VERSION 5.7 ;
BUSBITCHARS "[]" ;
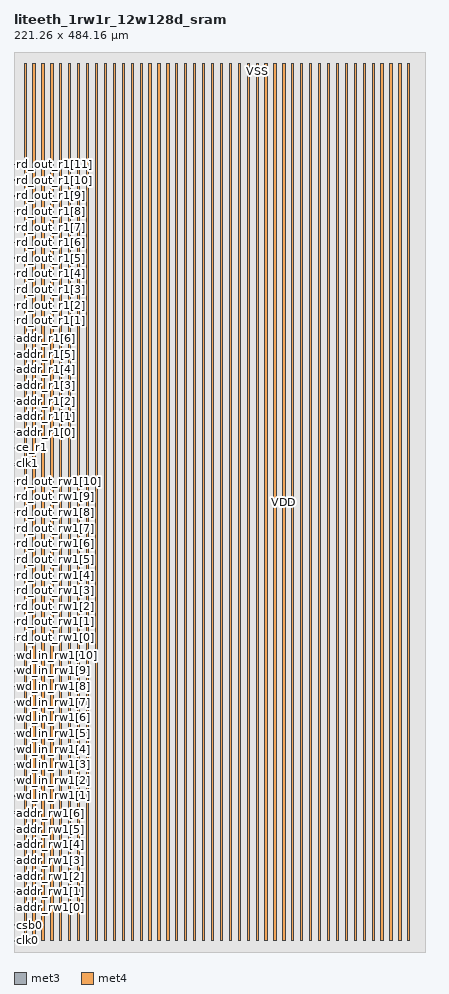
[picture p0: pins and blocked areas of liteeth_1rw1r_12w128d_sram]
MACRO liteeth_1rw1r_12w128d_sram
  FOREIGN liteeth_1rw1r_12w128d_sram 0 0 ;
  SYMMETRY X Y R90 ;
  SIZE 221.260 BY 484.160 ;
  CLASS BLOCK ;
  PIN clk0
    DIRECTION INPUT ;
    USE SIGNAL ;
    SHAPE ABUTMENT ;
    PORT
      LAYER met3 ;
      RECT 0.000 5.850 0.800 6.150 ;
    END
  END clk0
  PIN csb0
    DIRECTION INPUT ;
    USE SIGNAL ;
    SHAPE ABUTMENT ;
    PORT
      LAYER met3 ;
      RECT 0.000 14.250 0.800 14.550 ;
    END
  END csb0
  PIN we_in_rw1
    DIRECTION INPUT ;
    USE SIGNAL ;
    SHAPE ABUTMENT ;
    PORT
      LAYER met3 ;
      RECT 0.000 22.650 0.800 22.950 ;
    END
  END we_in_rw1
  PIN addr_rw1[0]
    DIRECTION INPUT ;
    USE SIGNAL ;
    SHAPE ABUTMENT ;
    PORT
      LAYER met3 ;
      RECT 0.000 23.850 0.800 24.150 ;
    END
  END addr_rw1[0]
  PIN addr_rw1[1]
    DIRECTION INPUT ;
    USE SIGNAL ;
    SHAPE ABUTMENT ;
    PORT
      LAYER met3 ;
      RECT 0.000 32.250 0.800 32.550 ;
    END
  END addr_rw1[1]
  PIN addr_rw1[2]
    DIRECTION INPUT ;
    USE SIGNAL ;
    SHAPE ABUTMENT ;
    PORT
      LAYER met3 ;
      RECT 0.000 40.650 0.800 40.950 ;
    END
  END addr_rw1[2]
  PIN addr_rw1[3]
    DIRECTION INPUT ;
    USE SIGNAL ;
    SHAPE ABUTMENT ;
    PORT
      LAYER met3 ;
      RECT 0.000 49.050 0.800 49.350 ;
    END
  END addr_rw1[3]
  PIN addr_rw1[4]
    DIRECTION INPUT ;
    USE SIGNAL ;
    SHAPE ABUTMENT ;
    PORT
      LAYER met3 ;
      RECT 0.000 57.450 0.800 57.750 ;
    END
  END addr_rw1[4]
  PIN addr_rw1[5]
    DIRECTION INPUT ;
    USE SIGNAL ;
    SHAPE ABUTMENT ;
    PORT
      LAYER met3 ;
      RECT 0.000 65.850 0.800 66.150 ;
    END
  END addr_rw1[5]
  PIN addr_rw1[6]
    DIRECTION INPUT ;
    USE SIGNAL ;
    SHAPE ABUTMENT ;
    PORT
      LAYER met3 ;
      RECT 0.000 74.250 0.800 74.550 ;
    END
  END addr_rw1[6]
  PIN wd_in_rw1[0]
    DIRECTION INPUT ;
    USE SIGNAL ;
    SHAPE ABUTMENT ;
    PORT
      LAYER met3 ;
      RECT 0.000 75.450 0.800 75.750 ;
    END
  END wd_in_rw1[0]
  PIN wd_in_rw1[1]
    DIRECTION INPUT ;
    USE SIGNAL ;
    SHAPE ABUTMENT ;
    PORT
      LAYER met3 ;
      RECT 0.000 83.850 0.800 84.150 ;
    END
  END wd_in_rw1[1]
  PIN wd_in_rw1[2]
    DIRECTION INPUT ;
    USE SIGNAL ;
    SHAPE ABUTMENT ;
    PORT
      LAYER met3 ;
      RECT 0.000 92.250 0.800 92.550 ;
    END
  END wd_in_rw1[2]
  PIN wd_in_rw1[3]
    DIRECTION INPUT ;
    USE SIGNAL ;
    SHAPE ABUTMENT ;
    PORT
      LAYER met3 ;
      RECT 0.000 100.650 0.800 100.950 ;
    END
  END wd_in_rw1[3]
  PIN wd_in_rw1[4]
    DIRECTION INPUT ;
    USE SIGNAL ;
    SHAPE ABUTMENT ;
    PORT
      LAYER met3 ;
      RECT 0.000 109.050 0.800 109.350 ;
    END
  END wd_in_rw1[4]
  PIN wd_in_rw1[5]
    DIRECTION INPUT ;
    USE SIGNAL ;
    SHAPE ABUTMENT ;
    PORT
      LAYER met3 ;
      RECT 0.000 117.450 0.800 117.750 ;
    END
  END wd_in_rw1[5]
  PIN wd_in_rw1[6]
    DIRECTION INPUT ;
    USE SIGNAL ;
    SHAPE ABUTMENT ;
    PORT
      LAYER met3 ;
      RECT 0.000 125.850 0.800 126.150 ;
    END
  END wd_in_rw1[6]
  PIN wd_in_rw1[7]
    DIRECTION INPUT ;
    USE SIGNAL ;
    SHAPE ABUTMENT ;
    PORT
      LAYER met3 ;
      RECT 0.000 134.250 0.800 134.550 ;
    END
  END wd_in_rw1[7]
  PIN wd_in_rw1[8]
    DIRECTION INPUT ;
    USE SIGNAL ;
    SHAPE ABUTMENT ;
    PORT
      LAYER met3 ;
      RECT 0.000 142.650 0.800 142.950 ;
    END
  END wd_in_rw1[8]
  PIN wd_in_rw1[9]
    DIRECTION INPUT ;
    USE SIGNAL ;
    SHAPE ABUTMENT ;
    PORT
      LAYER met3 ;
      RECT 0.000 151.050 0.800 151.350 ;
    END
  END wd_in_rw1[9]
  PIN wd_in_rw1[10]
    DIRECTION INPUT ;
    USE SIGNAL ;
    SHAPE ABUTMENT ;
    PORT
      LAYER met3 ;
      RECT 0.000 159.450 0.800 159.750 ;
    END
  END wd_in_rw1[10]
  PIN wd_in_rw1[11]
    DIRECTION INPUT ;
    USE SIGNAL ;
    SHAPE ABUTMENT ;
    PORT
      LAYER met3 ;
      RECT 0.000 167.850 0.800 168.150 ;
    END
  END wd_in_rw1[11]
  PIN rd_out_rw1[0]
    DIRECTION OUTPUT ;
    USE SIGNAL ;
    SHAPE ABUTMENT ;
    PORT
      LAYER met3 ;
      RECT 0.000 169.050 0.800 169.350 ;
    END
  END rd_out_rw1[0]
  PIN rd_out_rw1[1]
    DIRECTION OUTPUT ;
    USE SIGNAL ;
    SHAPE ABUTMENT ;
    PORT
      LAYER met3 ;
      RECT 0.000 177.450 0.800 177.750 ;
    END
  END rd_out_rw1[1]
  PIN rd_out_rw1[2]
    DIRECTION OUTPUT ;
    USE SIGNAL ;
    SHAPE ABUTMENT ;
    PORT
      LAYER met3 ;
      RECT 0.000 185.850 0.800 186.150 ;
    END
  END rd_out_rw1[2]
  PIN rd_out_rw1[3]
    DIRECTION OUTPUT ;
    USE SIGNAL ;
    SHAPE ABUTMENT ;
    PORT
      LAYER met3 ;
      RECT 0.000 194.250 0.800 194.550 ;
    END
  END rd_out_rw1[3]
  PIN rd_out_rw1[4]
    DIRECTION OUTPUT ;
    USE SIGNAL ;
    SHAPE ABUTMENT ;
    PORT
      LAYER met3 ;
      RECT 0.000 202.650 0.800 202.950 ;
    END
  END rd_out_rw1[4]
  PIN rd_out_rw1[5]
    DIRECTION OUTPUT ;
    USE SIGNAL ;
    SHAPE ABUTMENT ;
    PORT
      LAYER met3 ;
      RECT 0.000 211.050 0.800 211.350 ;
    END
  END rd_out_rw1[5]
  PIN rd_out_rw1[6]
    DIRECTION OUTPUT ;
    USE SIGNAL ;
    SHAPE ABUTMENT ;
    PORT
      LAYER met3 ;
      RECT 0.000 219.450 0.800 219.750 ;
    END
  END rd_out_rw1[6]
  PIN rd_out_rw1[7]
    DIRECTION OUTPUT ;
    USE SIGNAL ;
    SHAPE ABUTMENT ;
    PORT
      LAYER met3 ;
      RECT 0.000 227.850 0.800 228.150 ;
    END
  END rd_out_rw1[7]
  PIN rd_out_rw1[8]
    DIRECTION OUTPUT ;
    USE SIGNAL ;
    SHAPE ABUTMENT ;
    PORT
      LAYER met3 ;
      RECT 0.000 236.250 0.800 236.550 ;
    END
  END rd_out_rw1[8]
  PIN rd_out_rw1[9]
    DIRECTION OUTPUT ;
    USE SIGNAL ;
    SHAPE ABUTMENT ;
    PORT
      LAYER met3 ;
      RECT 0.000 244.650 0.800 244.950 ;
    END
  END rd_out_rw1[9]
  PIN rd_out_rw1[10]
    DIRECTION OUTPUT ;
    USE SIGNAL ;
    SHAPE ABUTMENT ;
    PORT
      LAYER met3 ;
      RECT 0.000 253.050 0.800 253.350 ;
    END
  END rd_out_rw1[10]
  PIN rd_out_rw1[11]
    DIRECTION OUTPUT ;
    USE SIGNAL ;
    SHAPE ABUTMENT ;
    PORT
      LAYER met3 ;
      RECT 0.000 261.450 0.800 261.750 ;
    END
  END rd_out_rw1[11]
  PIN clk1
    DIRECTION INPUT ;
    USE SIGNAL ;
    SHAPE ABUTMENT ;
    PORT
      LAYER met3 ;
      RECT 0.000 262.650 0.800 262.950 ;
    END
  END clk1
  PIN ce_r1
    DIRECTION INPUT ;
    USE SIGNAL ;
    SHAPE ABUTMENT ;
    PORT
      LAYER met3 ;
      RECT 0.000 271.050 0.800 271.350 ;
    END
  END ce_r1
  PIN addr_r1[0]
    DIRECTION INPUT ;
    USE SIGNAL ;
    SHAPE ABUTMENT ;
    PORT
      LAYER met3 ;
      RECT 0.000 279.450 0.800 279.750 ;
    END
  END addr_r1[0]
  PIN addr_r1[1]
    DIRECTION INPUT ;
    USE SIGNAL ;
    SHAPE ABUTMENT ;
    PORT
      LAYER met3 ;
      RECT 0.000 287.850 0.800 288.150 ;
    END
  END addr_r1[1]
  PIN addr_r1[2]
    DIRECTION INPUT ;
    USE SIGNAL ;
    SHAPE ABUTMENT ;
    PORT
      LAYER met3 ;
      RECT 0.000 296.250 0.800 296.550 ;
    END
  END addr_r1[2]
  PIN addr_r1[3]
    DIRECTION INPUT ;
    USE SIGNAL ;
    SHAPE ABUTMENT ;
    PORT
      LAYER met3 ;
      RECT 0.000 304.650 0.800 304.950 ;
    END
  END addr_r1[3]
  PIN addr_r1[4]
    DIRECTION INPUT ;
    USE SIGNAL ;
    SHAPE ABUTMENT ;
    PORT
      LAYER met3 ;
      RECT 0.000 313.050 0.800 313.350 ;
    END
  END addr_r1[4]
  PIN addr_r1[5]
    DIRECTION INPUT ;
    USE SIGNAL ;
    SHAPE ABUTMENT ;
    PORT
      LAYER met3 ;
      RECT 0.000 321.450 0.800 321.750 ;
    END
  END addr_r1[5]
  PIN addr_r1[6]
    DIRECTION INPUT ;
    USE SIGNAL ;
    SHAPE ABUTMENT ;
    PORT
      LAYER met3 ;
      RECT 0.000 329.850 0.800 330.150 ;
    END
  END addr_r1[6]
  PIN rd_out_r1[0]
    DIRECTION OUTPUT ;
    USE SIGNAL ;
    SHAPE ABUTMENT ;
    PORT
      LAYER met3 ;
      RECT 0.000 331.050 0.800 331.350 ;
    END
  END rd_out_r1[0]
  PIN rd_out_r1[1]
    DIRECTION OUTPUT ;
    USE SIGNAL ;
    SHAPE ABUTMENT ;
    PORT
      LAYER met3 ;
      RECT 0.000 339.450 0.800 339.750 ;
    END
  END rd_out_r1[1]
  PIN rd_out_r1[2]
    DIRECTION OUTPUT ;
    USE SIGNAL ;
    SHAPE ABUTMENT ;
    PORT
      LAYER met3 ;
      RECT 0.000 347.850 0.800 348.150 ;
    END
  END rd_out_r1[2]
  PIN rd_out_r1[3]
    DIRECTION OUTPUT ;
    USE SIGNAL ;
    SHAPE ABUTMENT ;
    PORT
      LAYER met3 ;
      RECT 0.000 356.250 0.800 356.550 ;
    END
  END rd_out_r1[3]
  PIN rd_out_r1[4]
    DIRECTION OUTPUT ;
    USE SIGNAL ;
    SHAPE ABUTMENT ;
    PORT
      LAYER met3 ;
      RECT 0.000 364.650 0.800 364.950 ;
    END
  END rd_out_r1[4]
  PIN rd_out_r1[5]
    DIRECTION OUTPUT ;
    USE SIGNAL ;
    SHAPE ABUTMENT ;
    PORT
      LAYER met3 ;
      RECT 0.000 373.050 0.800 373.350 ;
    END
  END rd_out_r1[5]
  PIN rd_out_r1[6]
    DIRECTION OUTPUT ;
    USE SIGNAL ;
    SHAPE ABUTMENT ;
    PORT
      LAYER met3 ;
      RECT 0.000 381.450 0.800 381.750 ;
    END
  END rd_out_r1[6]
  PIN rd_out_r1[7]
    DIRECTION OUTPUT ;
    USE SIGNAL ;
    SHAPE ABUTMENT ;
    PORT
      LAYER met3 ;
      RECT 0.000 389.850 0.800 390.150 ;
    END
  END rd_out_r1[7]
  PIN rd_out_r1[8]
    DIRECTION OUTPUT ;
    USE SIGNAL ;
    SHAPE ABUTMENT ;
    PORT
      LAYER met3 ;
      RECT 0.000 398.250 0.800 398.550 ;
    END
  END rd_out_r1[8]
  PIN rd_out_r1[9]
    DIRECTION OUTPUT ;
    USE SIGNAL ;
    SHAPE ABUTMENT ;
    PORT
      LAYER met3 ;
      RECT 0.000 406.650 0.800 406.950 ;
    END
  END rd_out_r1[9]
  PIN rd_out_r1[10]
    DIRECTION OUTPUT ;
    USE SIGNAL ;
    SHAPE ABUTMENT ;
    PORT
      LAYER met3 ;
      RECT 0.000 415.050 0.800 415.350 ;
    END
  END rd_out_r1[10]
  PIN rd_out_r1[11]
    DIRECTION OUTPUT ;
    USE SIGNAL ;
    SHAPE ABUTMENT ;
    PORT
      LAYER met3 ;
      RECT 0.000 423.450 0.800 423.750 ;
    END
  END rd_out_r1[11]
  PIN VSS
    DIRECTION INOUT ;
    USE GROUND ;
    PORT
      LAYER met4 ;
      RECT 5.400 6.000 6.600 478.160 ;
      RECT 15.000 6.000 16.200 478.160 ;
      RECT 24.600 6.000 25.800 478.160 ;
      RECT 34.200 6.000 35.400 478.160 ;
      RECT 43.800 6.000 45.000 478.160 ;
      RECT 53.400 6.000 54.600 478.160 ;
      RECT 63.000 6.000 64.200 478.160 ;
      RECT 72.600 6.000 73.800 478.160 ;
      RECT 82.200 6.000 83.400 478.160 ;
      RECT 91.800 6.000 93.000 478.160 ;
      RECT 101.400 6.000 102.600 478.160 ;
      RECT 111.000 6.000 112.200 478.160 ;
      RECT 120.600 6.000 121.800 478.160 ;
      RECT 130.200 6.000 131.400 478.160 ;
      RECT 139.800 6.000 141.000 478.160 ;
      RECT 149.400 6.000 150.600 478.160 ;
      RECT 159.000 6.000 160.200 478.160 ;
      RECT 168.600 6.000 169.800 478.160 ;
      RECT 178.200 6.000 179.400 478.160 ;
      RECT 187.800 6.000 189.000 478.160 ;
      RECT 197.400 6.000 198.600 478.160 ;
      RECT 207.000 6.000 208.200 478.160 ;
    END
  END VSS
  PIN VDD
    DIRECTION INOUT ;
    USE POWER ;
    PORT
      LAYER met4 ;
      RECT 10.200 6.000 11.400 478.160 ;
      RECT 19.800 6.000 21.000 478.160 ;
      RECT 29.400 6.000 30.600 478.160 ;
      RECT 39.000 6.000 40.200 478.160 ;
      RECT 48.600 6.000 49.800 478.160 ;
      RECT 58.200 6.000 59.400 478.160 ;
      RECT 67.800 6.000 69.000 478.160 ;
      RECT 77.400 6.000 78.600 478.160 ;
      RECT 87.000 6.000 88.200 478.160 ;
      RECT 96.600 6.000 97.800 478.160 ;
      RECT 106.200 6.000 107.400 478.160 ;
      RECT 115.800 6.000 117.000 478.160 ;
      RECT 125.400 6.000 126.600 478.160 ;
      RECT 135.000 6.000 136.200 478.160 ;
      RECT 144.600 6.000 145.800 478.160 ;
      RECT 154.200 6.000 155.400 478.160 ;
      RECT 163.800 6.000 165.000 478.160 ;
      RECT 173.400 6.000 174.600 478.160 ;
      RECT 183.000 6.000 184.200 478.160 ;
      RECT 192.600 6.000 193.800 478.160 ;
      RECT 202.200 6.000 203.400 478.160 ;
      RECT 211.800 6.000 213.000 478.160 ;
    END
  END VDD
  OBS
    LAYER met1 ;
    RECT 0 0 221.260 484.160 ;
    LAYER met2 ;
    RECT 0 0 221.260 484.160 ;
    LAYER met3 ;
    RECT 0.800 0 221.260 484.160 ;
    LAYER met4 ;
    RECT 0 0 221.260 484.160 ;
    LAYER OVERLAP ;
    RECT 0 0 221.260 484.160 ;
  END
END liteeth_1rw1r_12w128d_sram

END LIBRARY
